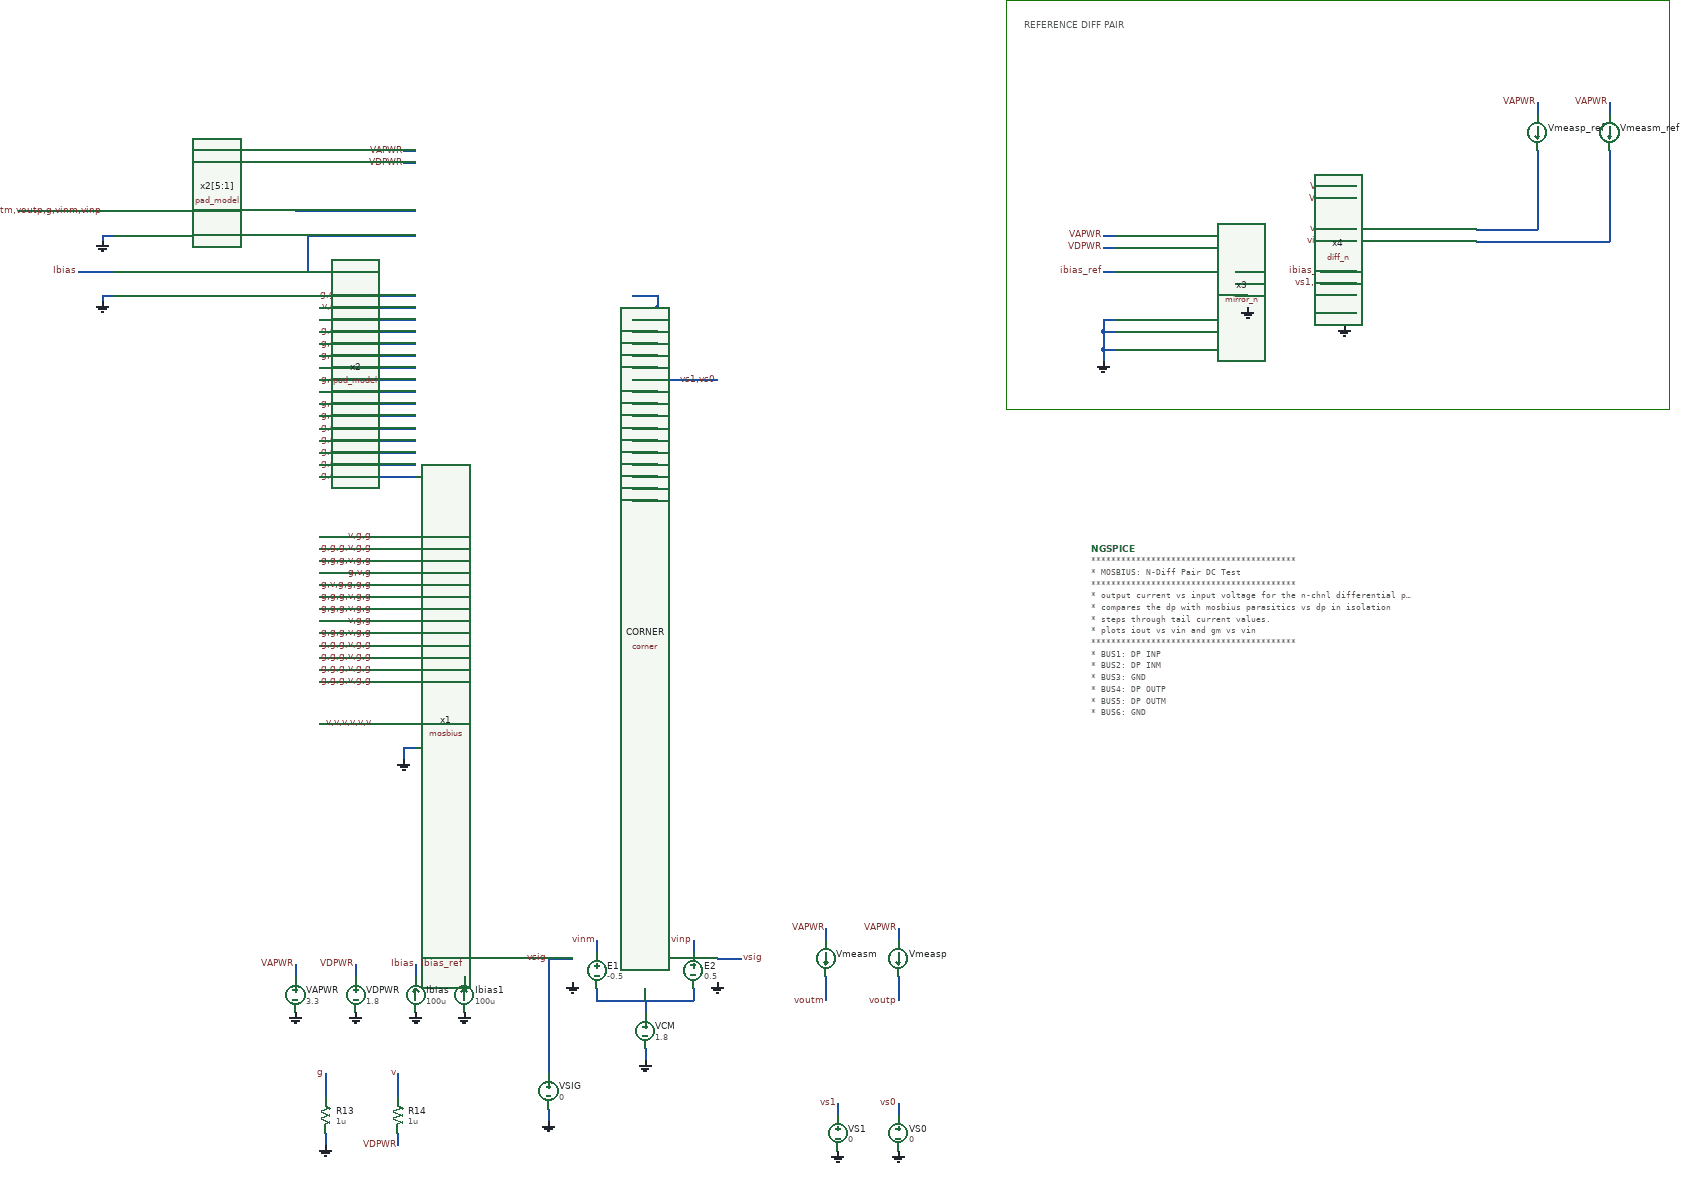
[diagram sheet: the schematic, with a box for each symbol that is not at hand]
v {xschem version=3.1.0 file_version=1.2
}
G {}
K {}
V {}
S {}
E {}
L 4 1280 -1500 1280 -820 {}
L 4 1280 -1500 2380 -1500 {}
L 4 1280 -820 2380 -820 {}
L 4 2380 -1500 2380 -820 {}
T {REFERENCE DIFF PAIR} 1310 -1470 0 0 0.4 0.4 {}
N 100 100 100 120 {
lab=VAPWR}
N 200 100 200 120 {
lab=VDPWR}
N 280 -1230 300 -1230 {
lab=VDPWR}
N 280 -1250 300 -1250 {
lab=VAPWR}
N 280 -260 280 -240 {
lab=GND}
N 280 -260 300 -260 {
lab=GND}
N 300 100 300 120 {
lab=Ibias}
N 660 -970 700 -970 {
lab=GND}
N 660 -950 700 -950 {
lab=GND}
N 660 -930 700 -930 {
lab=GND}
N 660 -910 700 -910 {
lab=GND}
N 660 -890 700 -890 {
lab=GND}
N 660 -850 700 -850 {
lab=GND}
N 660 -810 700 -810 {
lab=GND}
N 660 -790 700 -790 {
lab=GND}
N 660 -770 700 -770 {
lab=GND}
N 660 -750 700 -750 {
lab=GND}
N 660 -730 700 -730 {
lab=GND}
N 660 -710 700 -710 {
lab=GND}
N 660 -690 700 -690 {
lab=GND}
N 660 -670 700 -670 {
lab=GND}
N 700 -970 700 -640 {
lab=GND}
N 680 240 680 260 {
lab=GND}
N 760 60 760 80 {
lab=vinp}
N 660 -990 700 -990 {
lab=GND}
N 700 -990 700 -970 {
lab=GND}
N 150 380 150 400 {
lab=GND}
N 150 280 150 320 {
lab=g}
N 270 280 270 320 {
lab=v}
N 270 380 270 400 {
lab=VDPWR}
N 140 -370 300 -370 {
lab=g,g,g,v,g,g}
N 140 -390 300 -390 {
lab=g,g,g,v,g,g}
N 140 -410 300 -410 {
lab=g,g,g,v,g,g}
N 140 -430 300 -430 {
lab=g,g,g,v,g,g}
N 140 -450 300 -450 {
lab=g,g,g,v,g,g}
N 140 -470 300 -470 {
lab=v,g,g}
N 140 -490 300 -490 {
lab=g,g,g,v,g,g}
N 140 -510 300 -510 {
lab=g,g,g,v,g,g}
N 140 -530 300 -530 {
lab=g,v,g,g,g,g}
N 140 -550 300 -550 {
lab=g,v,g}
N 140 -570 300 -570 {
lab=g,g,g,v,g,g}
N 140 -590 300 -590 {
lab=g,g,g,v,g,g}
N 140 -610 300 -610 {
lab=v,g,g}
N 140 -710 300 -710 {
lab=g,g,g,v,g,g}
N 140 -730 300 -730 {
lab=g,g,g,v,g,g}
N 140 -750 300 -750 {
lab=g,g,g,v,g,g}
N 140 -770 300 -770 {
lab=g,g,g,v,g,g}
N 140 -790 300 -790 {
lab=g,g,g,v,g,g}
N 140 -810 300 -810 {
lab=g,g,g,v,g,g}
N 140 -830 300 -830 {
lab=g,g,g,v,g,g}
N 140 -870 300 -870 {
lab=g,g,v,g,g,g}
N 140 -910 300 -910 {
lab=g,g,g,v,g,g}
N 140 -930 300 -930 {
lab=g,g,g,v,g,g}
N 140 -1010 300 -1010 {
lab=g,g,g,g,g,g}
N 140 -850 300 -850 {
lab=v,g,g}
N 140 -890 300 -890 {
lab=g,g,v}
N 140 -300 300 -300 {
lab=v,v,v,v,v,v}
N 140 -990 300 -990 {
lab=v,g,g,v,g,g}
N 140 -970 300 -970 {
lab=v,g,g}
N 140 -950 300 -950 {
lab=g,g,g,v,g,g}
N 1840 -1170 1860 -1170 {
lab=VDPWR}
N 1840 -1190 1860 -1190 {
lab=VAPWR}
N 1840 -980 1840 -960 {
lab=GND}
N 1840 -980 1860 -980 {
lab=GND}
N 1440 -1090 1460 -1090 {
lab=VDPWR}
N 1440 -1110 1460 -1110 {
lab=VAPWR}
N 1440 -920 1440 -900 {
lab=GND}
N 1440 -920 1460 -920 {
lab=GND}
N 1440 -950 1460 -950 {
lab=GND}
N 1440 -950 1440 -920 {
lab=GND}
N 1440 -970 1460 -970 {
lab=GND}
N 1440 -970 1440 -950 {
lab=GND}
N 1680 -1030 1680 -990 {
lab=GND}
N 1660 -1030 1680 -1030 {
lab=GND}
N 1660 -1010 1680 -1010 {
lab=GND}
N 380 100 380 120 {
lab=ibias_ref}
N 1440 -1050 1460 -1050 {
lab=ibias_ref}
N 1840 -1010 1860 -1010 {
lab=GND}
N 1840 -1010 1840 -980 {
lab=GND}
N 1800 -1030 1860 -1030 {
lab=vs1,vs0}
N 1820 -1120 1860 -1120 {
lab=vinp}
N 1820 -1100 1860 -1100 {
lab=vinm}
N 1800 -1050 1860 -1050 {
lab=ibias_ref}
N -360 -1150 -200 -1150 {
lab=voutm,voutp,g,vinm,vinp}
N 100 -1150 300 -1150 {
lab=#net1}
N -260 -1050 -200 -1050 {
lab=Ibias}
N 100 -1050 120 -1050 {
lab=#net2}
N 120 -1110 120 -1050 {
lab=#net2}
N 120 -1110 300 -1110 {
lab=#net2}
N -220 -1010 -220 -1000 {
lab=GND}
N -220 -1010 -200 -1010 {
lab=GND}
N -220 -1110 -220 -1100 {
lab=GND}
N -220 -1110 -200 -1110 {
lab=GND}
N 600 60 600 80 {
lab=vinm}
N 600 140 600 160 {
lab=#net3}
N 600 160 760 160 {
lab=#net3}
N 760 140 760 160 {
lab=#net3}
N 680 160 680 180 {
lab=#net3}
N 1100 40 1100 60 {
lab=VAPWR}
N 980 40 980 60 {
lab=VAPWR}
N 980 120 980 160 {
lab=voutm}
N 1100 120 1100 160 {
lab=voutp}
N 2280 -1330 2280 -1310 {
lab=VAPWR}
N 2160 -1330 2160 -1310 {
lab=VAPWR}
N 2060 -1120 2160 -1120 {
lab=#net4}
N 2160 -1250 2160 -1120 {
lab=#net4}
N 2060 -1100 2280 -1100 {
lab=#net5}
N 2280 -1250 2280 -1100 {
lab=#net5}
N 660 -1010 700 -1010 {
lab=GND}
N 700 -1010 700 -990 {
lab=GND}
N 660 -870 800 -870 {
lab=vs1,vs0}
N 660 -830 700 -830 {
lab=GND}
N 520 340 520 360 {
lab=GND}
N 520 90 520 280 {
lab=vsig}
N 520 90 560 90 {
lab=vsig}
N 800 90 840 90 {
lab=vsig}
N 1000 330 1000 350 {
lab=vs1}
N 1100 330 1100 350 {
lab=vs0}
N 1660 -1050 1680 -1050 {
lab=GND}
N 1680 -1050 1680 -1030 {
lab=GND}
C {mosbius.sym} 300 -240 0 0 {name=x1}
C {devices/vsource.sym} 100 150 0 0 {name=VAPWR value=3.3}
C {devices/gnd.sym} 100 180 0 0 {name=l1 lab=GND}
C {devices/lab_pin.sym} 100 100 1 0 {name=p2 sig_type=std_logic lab=VAPWR}
C {devices/vsource.sym} 200 150 0 0 {name=VDPWR value=1.8}
C {devices/gnd.sym} 200 180 0 0 {name=l2 lab=GND}
C {devices/lab_pin.sym} 200 100 1 0 {name=p3 sig_type=std_logic lab=VDPWR}
C {devices/lab_pin.sym} 280 -1250 0 0 {name=p4 sig_type=std_logic lab=VAPWR}
C {devices/lab_pin.sym} 280 -1230 0 0 {name=p5 sig_type=std_logic lab=VDPWR}
C {devices/gnd.sym} 280 -240 0 0 {name=l3 lab=GND}
C {devices/isource.sym} 300 150 2 1 {name=Ibias value=100u}
C {devices/gnd.sym} 300 180 0 0 {name=l4 lab=GND}
C {devices/lab_pin.sym} 300 100 1 0 {name=p1 sig_type=std_logic lab=Ibias}
C {devices/gnd.sym} 700 -640 0 0 {name=l5 lab=GND}
C {devices/vsource.sym} 520 310 0 0 {name=VSIG value=0}
C {devices/vsource.sym} 680 210 0 0 {name=VCM value=1.8}
C {devices/gnd.sym} 680 260 0 0 {name=l9 lab=GND}
C {devices/lab_pin.sym} 760 60 1 0 {name=p10 sig_type=std_logic lab=vinp}
C {sky130_fd_pr/corner.sym} 950 -350 0 0 {name=CORNER only_toplevel=true corner=tt}
C {devices/code_shown.sym} 1420 -590 0 0 {name=NGSPICE only_toplevel=true value=
"
*****************************************
* MOSBIUS: N-Diff Pair DC Test
*****************************************
* output current vs input voltage for the n-chnl differential pair.
* compares the dp with mosbius parasitics vs dp in isolation
* steps through tail current values.
* plots iout vs vin and gm vs vin
*****************************************
* BUS1: DP INP
* BUS2: DP INM
* BUS3: GND
* BUS4: DP OUTP
* BUS5: DP OUTM
* BUS6: GND
*****************************************
.control
   save all
   set temp = 27
   repeat 2
      repeat 2
         dc vsig -1 1 0.01
         alter VS0 1.8
      end
      alter VS0 0
      alter VS1 1.8
   end
   let mosb_200u = dc1.i(vmeasp)-dc1.i(vmeasm)
   let base_200u = dc1.i(vmeasp_ref)-dc1.i(vmeasm_ref)
   let mosb_400u = dc2.i(vmeasp)-dc2.i(vmeasm)
   let base_400u = dc2.i(vmeasp_ref)-dc2.i(vmeasm_ref)
   let mosb_600u = dc3.i(vmeasp)-dc3.i(vmeasm)
   let base_600u = dc3.i(vmeasp_ref)-dc3.i(vmeasm_ref)
   let mosb_800u = dc4.i(vmeasp)-dc4.i(vmeasm)
   let base_800u = dc4.i(vmeasp_ref)-dc4.i(vmeasm_ref)
   let mosb_gm_200u = deriv(mosb_200u)
   let base_gm_200u = deriv(base_200u)
   let mosb_gm_400u = deriv(mosb_400u)
   let base_gm_400u = deriv(base_400u)
   let mosb_gm_600u = deriv(mosb_600u)
   let base_gm_600u = deriv(base_600u)
   let mosb_gm_800u = deriv(mosb_800u)
   let base_gm_800u = deriv(base_800u)
   plot mosb_200u base_200u mosb_400u base_400u mosb_600u base_600u mosb_800u base_800u
   plot mosb_gm_200u base_gm_200u mosb_gm_400u base_gm_400u mosb_gm_600u base_gm_600u mosb_gm_800u base_gm_800u
.endc
"}
C {devices/lab_wire.sym} 230 -370 0 0 {name=p16 sig_type=std_logic lab=g,g,g,v,g,g}
C {devices/gnd.sym} 150 400 0 0 {name=l10 lab=GND}
C {devices/res.sym} 150 350 0 0 {name=R13
value=1u
footprint=1206
device=resistor
m=1}
C {devices/lab_pin.sym} 150 280 0 0 {name=p17 sig_type=std_logic lab=g}
C {devices/res.sym} 270 350 0 0 {name=R14
value=1u
footprint=1206
device=resistor
m=1}
C {devices/lab_pin.sym} 270 400 3 0 {name=p18 sig_type=std_logic lab=VDPWR}
C {devices/lab_pin.sym} 270 280 0 0 {name=p19 sig_type=std_logic lab=v}
C {devices/lab_wire.sym} 230 -390 0 0 {name=p20 sig_type=std_logic lab=g,g,g,v,g,g}
C {devices/lab_wire.sym} 230 -410 0 0 {name=p21 sig_type=std_logic lab=g,g,g,v,g,g}
C {devices/lab_wire.sym} 230 -430 0 0 {name=p22 sig_type=std_logic lab=g,g,g,v,g,g}
C {devices/lab_wire.sym} 230 -450 0 0 {name=p24 sig_type=std_logic lab=g,g,g,v,g,g}
C {devices/lab_wire.sym} 230 -470 0 0 {name=p27 sig_type=std_logic lab=v,g,g}
C {devices/lab_wire.sym} 230 -490 0 0 {name=p39 sig_type=std_logic lab=g,g,g,v,g,g}
C {devices/lab_wire.sym} 230 -510 0 0 {name=p40 sig_type=std_logic lab=g,g,g,v,g,g}
C {devices/lab_wire.sym} 230 -530 0 0 {name=p41 sig_type=std_logic lab=g,v,g,g,g,g}
C {devices/lab_wire.sym} 230 -550 0 0 {name=p42 sig_type=std_logic lab=g,v,g}
C {devices/lab_wire.sym} 230 -570 0 0 {name=p43 sig_type=std_logic lab=g,g,g,v,g,g}
C {devices/lab_wire.sym} 230 -590 0 0 {name=p44 sig_type=std_logic lab=g,g,g,v,g,g}
C {devices/lab_wire.sym} 230 -610 0 0 {name=p45 sig_type=std_logic lab=v,g,g}
C {devices/lab_wire.sym} 230 -710 0 0 {name=p46 sig_type=std_logic lab=g,g,g,v,g,g}
C {devices/lab_wire.sym} 230 -730 0 0 {name=p47 sig_type=std_logic lab=g,g,g,v,g,g}
C {devices/lab_wire.sym} 230 -750 0 0 {name=p48 sig_type=std_logic lab=g,g,g,v,g,g}
C {devices/lab_wire.sym} 230 -770 0 0 {name=p49 sig_type=std_logic lab=g,g,g,v,g,g}
C {devices/lab_wire.sym} 230 -790 0 0 {name=p50 sig_type=std_logic lab=g,g,g,v,g,g}
C {devices/lab_wire.sym} 230 -810 0 0 {name=p51 sig_type=std_logic lab=g,g,g,v,g,g}
C {devices/lab_wire.sym} 230 -830 0 0 {name=p52 sig_type=std_logic lab=g,g,g,v,g,g}
C {devices/lab_wire.sym} 230 -870 0 0 {name=p53 sig_type=std_logic lab=g,g,v,g,g,g}
C {devices/lab_wire.sym} 230 -910 0 0 {name=p54 sig_type=std_logic lab=g,g,g,v,g,g}
C {devices/lab_wire.sym} 230 -930 0 0 {name=p55 sig_type=std_logic lab=g,g,g,v,g,g}
C {devices/lab_wire.sym} 230 -1010 0 0 {name=p56 sig_type=std_logic lab=g,g,g,g,g,g}
C {devices/lab_wire.sym} 230 -850 0 0 {name=p57 sig_type=std_logic lab=v,g,g}
C {devices/lab_wire.sym} 230 -890 0 0 {name=p58 sig_type=std_logic lab=g,g,v}
C {devices/lab_wire.sym} 230 -300 0 0 {name=p25 sig_type=std_logic lab=v,v,v,v,v,v}
C {devices/lab_wire.sym} 230 -990 0 0 {name=p11 sig_type=std_logic lab=v,g,g,v,g,g}
C {devices/lab_wire.sym} 230 -970 0 0 {name=p15 sig_type=std_logic lab=v,g,g}
C {devices/lab_wire.sym} 230 -950 0 0 {name=p7 sig_type=std_logic lab=g,g,g,v,g,g}
C {devices/lab_pin.sym} 1840 -1190 0 0 {name=p13 sig_type=std_logic lab=VAPWR}
C {devices/lab_pin.sym} 1840 -1170 0 0 {name=p23 sig_type=std_logic lab=VDPWR}
C {devices/gnd.sym} 1840 -960 0 0 {name=l7 lab=GND}
C {mirror_n.sym} 1510 -1050 0 0 {name=x3}
C {devices/lab_pin.sym} 1440 -1110 0 0 {name=p26 sig_type=std_logic lab=VAPWR}
C {devices/lab_pin.sym} 1440 -1090 0 0 {name=p29 sig_type=std_logic lab=VDPWR}
C {devices/gnd.sym} 1440 -900 0 0 {name=l8 lab=GND}
C {devices/gnd.sym} 1680 -990 0 0 {name=l11 lab=GND}
C {devices/isource.sym} 380 150 2 1 {name=Ibias1 value=100u}
C {devices/gnd.sym} 380 180 0 0 {name=l12 lab=GND}
C {devices/lab_pin.sym} 380 100 1 0 {name=p30 sig_type=std_logic lab=ibias_ref}
C {devices/lab_pin.sym} 1440 -1050 0 0 {name=p31 sig_type=std_logic lab=ibias_ref}
C {devices/lab_pin.sym} 1820 -1120 2 1 {name=p12 sig_type=std_logic lab=vinp}
C {devices/lab_pin.sym} 1820 -1100 2 1 {name=p32 sig_type=std_logic lab=vinm}
C {devices/lab_wire.sym} 1820 -1030 0 0 {name=p35 sig_type=std_logic lab=vs1,vs0}
C {devices/lab_wire.sym} 1820 -1050 0 0 {name=p36 sig_type=std_logic lab=ibias_ref}
C {pad_model.sym} -50 -1130 0 0 {name=x2[5:1]}
C {devices/lab_wire.sym} -220 -1150 0 0 {name=p9 sig_type=std_logic lab=voutm,voutp,g,vinm,vinp}
C {pad_model.sym} -50 -1030 0 0 {name=x2}
C {devices/lab_pin.sym} -260 -1050 0 0 {name=p6 sig_type=std_logic lab=Ibias}
C {devices/gnd.sym} -220 -1100 0 0 {name=l14 lab=GND}
C {devices/gnd.sym} -220 -1000 0 0 {name=l15 lab=GND}
C {devices/lab_pin.sym} 600 60 1 0 {name=p8 sig_type=std_logic lab=vinm}
C {devices/ammeter.sym} 980 90 0 0 {name=Vmeasm}
C {devices/ammeter.sym} 1100 90 0 0 {name=Vmeasp}
C {devices/lab_pin.sym} 980 40 1 0 {name=p28 sig_type=std_logic lab=VAPWR}
C {devices/lab_pin.sym} 1100 40 1 0 {name=p37 sig_type=std_logic lab=VAPWR}
C {devices/lab_pin.sym} 980 160 3 0 {name=p38 sig_type=std_logic lab=voutm}
C {devices/lab_pin.sym} 1100 160 3 0 {name=p59 sig_type=std_logic lab=voutp}
C {diff_n.sym} 1960 -1070 0 0 {name=x4}
C {devices/ammeter.sym} 2160 -1280 0 0 {name=Vmeasp_ref}
C {devices/ammeter.sym} 2280 -1280 0 0 {name=Vmeasm_ref}
C {devices/lab_pin.sym} 2160 -1330 1 0 {name=p33 sig_type=std_logic lab=VAPWR}
C {devices/lab_pin.sym} 2280 -1330 1 0 {name=p34 sig_type=std_logic lab=VAPWR}
C {devices/lab_wire.sym} 800 -870 0 0 {name=p14 sig_type=std_logic lab=vs1,vs0}
C {devices/vcvs.sym} 600 110 0 0 {name=E1 value=-0.5}
C {devices/vcvs.sym} 760 110 0 1 {name=E2 value=0.5}
C {devices/gnd.sym} 520 360 0 0 {name=l6 lab=GND}
C {devices/gnd.sym} 560 130 0 0 {name=l13 lab=GND}
C {devices/gnd.sym} 800 130 0 0 {name=l16 lab=GND}
C {devices/lab_pin.sym} 520 90 0 0 {name=p60 sig_type=std_logic lab=vsig}
C {devices/lab_pin.sym} 840 90 0 1 {name=p61 sig_type=std_logic lab=vsig}
C {devices/vsource.sym} 1000 380 0 0 {name=VS1 value=0}
C {devices/gnd.sym} 1000 410 0 0 {name=l17 lab=GND}
C {devices/lab_pin.sym} 1000 330 1 0 {name=p62 sig_type=std_logic lab=vs1}
C {devices/vsource.sym} 1100 380 0 0 {name=VS0 value=0}
C {devices/gnd.sym} 1100 410 0 0 {name=l18 lab=GND}
C {devices/lab_pin.sym} 1100 330 1 0 {name=p63 sig_type=std_logic lab=vs0}
